# Hand-written edge cases for the #43 parser gate: valid for both Limbo and DesignReader.
VERSION 5.8 ;
BUSBITCHARS "[]" ;
DIVIDERCHAR "/" ;
UNITS
  DATABASE MICRONS 2000 ;
END UNITS

MANUFACTURINGGRID 0.005 ;

PROPERTYDEFINITIONS
  LAYER LEF57_SPACING STRING ;
  LIBRARY LEF58_CELLEDGESPACINGTABLE STRING
"CELLEDGESPACINGTABLE
    EDGETYPE 1 2 0.400 ;
;" ;
END PROPERTYDEFINITIONS

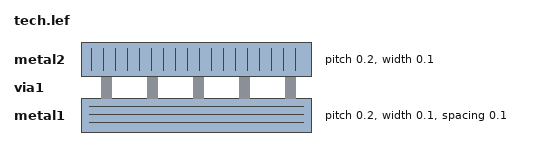
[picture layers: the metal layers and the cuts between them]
LAYER metal1
  TYPE ROUTING ;
  DIRECTION HORIZONTAL ;
  PITCH 0.200 ;
  WIDTH 0.100 ;
  SPACING 0.100 ;
  PROPERTY LEF57_SPACING "SPACING 0.1 ENDOFLINE 0.1 WITHIN 0.05 ;" ;
END metal1

LAYER via1
  TYPE CUT ;
END via1

LAYER metal2
  TYPE ROUTING ;
  DIRECTION VERTICAL ;
  PITCH 0.200 ;
  WIDTH 0.100 ;
END metal2

VIA via12 DEFAULT
  LAYER metal1 ;
    RECT -0.05 -0.05 0.05 0.05 ;
  LAYER via1 ;
    RECT -0.05 -0.05 0.05 0.05 ;
  LAYER metal2 ;
    RECT -0.05 -0.05 0.05 0.05 ;
END via12

VIARULE via12gen GENERATE
  LAYER metal1 ;
    ENCLOSURE 0 0 ;
  LAYER metal2 ;
    ENCLOSURE 0 0 ;
  LAYER via1 ;
    RECT -0.05 -0.05 0.05 0.05 ;
    SPACING 0.2 BY 0.2 ;
END via12gen

NONDEFAULTRULE wide
  LAYER metal1
    WIDTH 0.2 ;
  END metal1
END wide

SITE pad
  CLASS PAD ;
  SIZE 10.0 BY 10.0 ;
END pad

SITE core
  SIZE 0.20 BY 2.00 ;
  CLASS CORE ;
  SYMMETRY Y ;
END core

END LIBRARY
